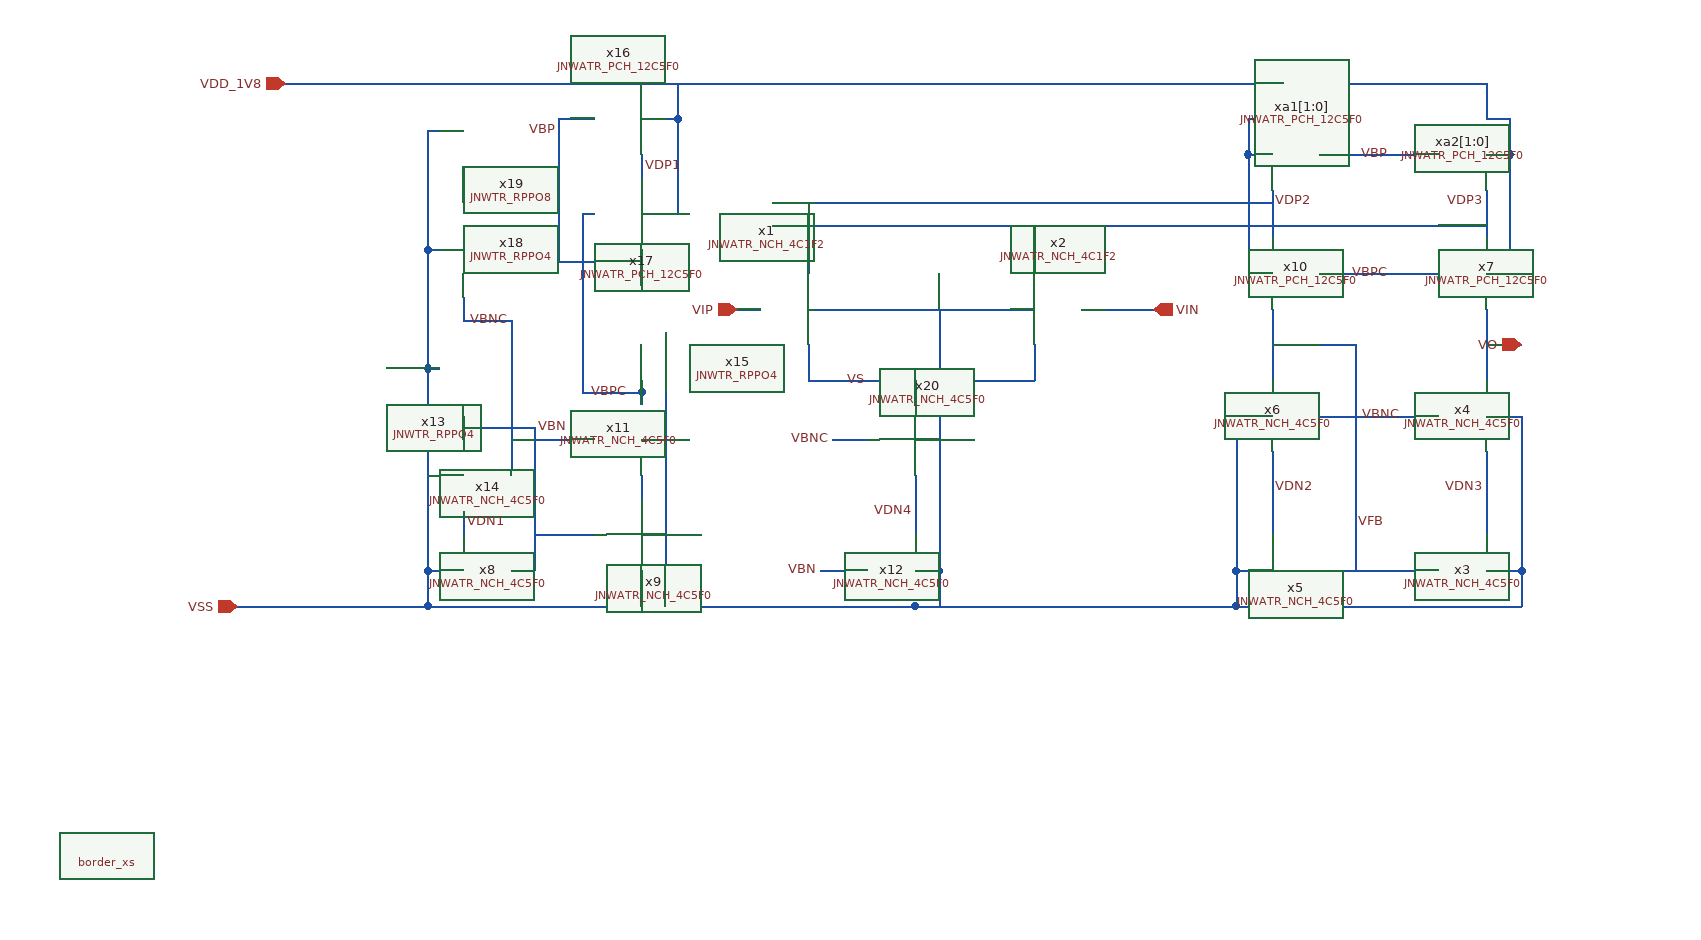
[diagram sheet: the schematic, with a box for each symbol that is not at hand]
v {xschem version=3.4.8RC file_version=1.3}
G {}
K {}
V {}
S {}
F {}
E {}
N 590 -460 780 -460 {lab=VSS}
N 1160 -240 1190 -240 {lab=VSS}
N 1190 -240 1190 -210 {lab=VSS}
N 1160 -210 1190 -210 {lab=VSS}
N 1160 -340 1160 -270 {lab=VDN3}
N 1160 -370 1190 -370 {lab=VSS}
N 1190 -370 1190 -240 {lab=VSS}
N 950 -240 980 -240 {lab=VSS}
N 950 -240 950 -210 {lab=VSS}
N 950 -210 980 -210 {lab=VSS}
N 980 -340 980 -270 {lab=VDN2}
N 950 -370 980 -370 {lab=VSS}
N 950 -370 950 -240 {lab=VSS}
N 1020 -370 1120 -370 {lab=VBNC}
N 1020 -240 1120 -240 {lab=VFB}
N 980 -210 1160 -210 {lab=VSS}
N 1160 -560 1160 -520 {lab=VDP3}
N 1160 -490 1180 -490 {lab=VDD_1V8}
N 1180 -590 1180 -490 {lab=VDD_1V8}
N 1160 -590 1180 -590 {lab=VDD_1V8}
N 1180 -620 1180 -590 {lab=VDD_1V8}
N 1160 -620 1180 -620 {lab=VDD_1V8}
N 980 -560 980 -520 {lab=VDP2}
N 960 -490 980 -490 {lab=VDD_1V8}
N 960 -590 960 -490 {lab=VDD_1V8}
N 960 -590 980 -590 {lab=VDD_1V8}
N 960 -620 960 -590 {lab=VDD_1V8}
N 960 -620 980 -620 {lab=VDD_1V8}
N 980 -460 980 -410 {lab=VFB}
N 1160 -460 1160 -400 {lab=VO}
N 1020 -590 1120 -590 {lab=VBP}
N 1020 -490 1120 -490 {lab=VBPC}
N 980 -410 980 -400 {lab=VFB}
N 1050 -430 1050 -240 {lab=VFB}
N 980 -430 1050 -430 {lab=VFB}
N 780 -430 780 -400 {lab=VS}
N 590 -400 780 -400 {lab=VS}
N 590 -430 590 -400 {lab=VS}
N 680 -240 700 -240 {lab=VSS}
N 700 -240 700 -210 {lab=VSS}
N 680 -210 700 -210 {lab=VSS}
N 680 -210 950 -210 {lab=VSS}
N 700 -460 700 -240 {lab=VSS}
N 820 -460 860 -460 {lab=VIN}
N 980 -650 980 -620 {lab=VDD_1V8}
N 980 -650 1160 -650 {lab=VDD_1V8}
N 1160 -650 1160 -620 {lab=VDD_1V8}
N 150 -650 990 -650 {lab=VDD_1V8}
N 270 -240 300 -240 {lab=VSS}
N 270 -240 270 -210 {lab=VSS}
N 270 -210 300 -210 {lab=VSS}
N 300 -210 680 -210 {lab=VSS}
N 270 -410 280 -410 {lab=VSS}
N 270 -410 270 -240 {lab=VSS}
N 300 -290 300 -270 {lab=VDN1}
N 270 -320 300 -320 {lab=VSS}
N 300 -370 300 -350 {lab=VBN}
N 300 -360 360 -360 {lab=VBN}
N 360 -360 360 -240 {lab=VBN}
N 340 -240 360 -240 {lab=VBN}
N 340 -450 340 -320 {lab=VBNC}
N 300 -450 340 -450 {lab=VBNC}
N 450 -510 450 -480 {lab=VBP}
N 450 -540 480 -540 {lab=VDD_1V8}
N 480 -620 480 -540 {lab=VDD_1V8}
N 450 -620 480 -620 {lab=VDD_1V8}
N 450 -590 450 -570 {lab=VDP1}
N 380 -620 410 -620 {lab=VBP}
N 450 -400 450 -390 {lab=VBPC}
N 380 -500 450 -500 {lab=VBP}
N 380 -620 380 -500 {lab=VBP}
N 400 -540 410 -540 {lab=VBPC}
N 400 -540 400 -390 {lab=VBPC}
N 400 -390 450 -390 {lab=VBPC}
N 300 -470 300 -450 {lab=VBNC}
N 270 -510 280 -510 {lab=VSS}
N 270 -510 270 -410 {lab=VSS}
N 470 -440 470 -210 {lab=VSS}
N 110 -210 270 -210 {lab=VSS}
N 530 -460 550 -460 {lab=VIP}
N 860 -460 880 -460 {lab=VIN}
N 1160 -430 1190 -430 {lab=VO}
N 600 -240 640 -240 {lab=VBN}
N 450 -240 450 -210 {lab=VSS}
N 360 -270 410 -270 {lab=VBN}
N 450 -270 470 -270 {lab=VSS}
N 560 -550 980 -550 {lab=VDP2}
N 560 -530 1160 -530 {lab=VDP3}
N 780 -530 780 -490 {lab=VDP3}
N 590 -550 590 -490 {lab=VDP2}
N 450 -350 470 -350 {lab=VSS}
N 450 -320 450 -300 {lab=#net1}
N 450 -390 450 -380 {lab=VBPC}
N 340 -350 410 -350 {lab=VBNC}
N 480 -650 480 -620 {lab=VDD_1V8}
N 300 -570 300 -550 {lab=#net2}
N 270 -610 270 -510 {lab=VSS}
N 270 -610 280 -610 {lab=VSS}
N 680 -350 700 -350 {lab=VSS}
N 680 -320 680 -270 {lab=VDN4}
N 680 -400 680 -380 {lab=VS}
N 610 -350 640 -350 {lab=VBNC}
C {cborder/border_xs.sym} 0 0 0 0 {
user="Carsten Wulff"
company="Carsten Wulff Software"}
C {devices/ipin.sym} 150 -650 0 0 {name=p1 lab=VDD_1V8}
C {devices/ipin.sym} 110 -210 0 0 {name=p2 lab=VSS}
C {JNW_ATR_SKY130A/JNWATR_NCH_4C1F2.sym} 550 -460 0 0 {name=x1 }
C {JNW_ATR_SKY130A/JNWATR_NCH_4C1F2.sym} 820 -460 0 1 {name=x2 }
C {JNW_ATR_SKY130A/JNWATR_NCH_4C5F0.sym} 1120 -240 0 0 {name=x3 }
C {JNW_ATR_SKY130A/JNWATR_NCH_4C5F0.sym} 1120 -370 0 0 {name=x4 }
C {JNW_ATR_SKY130A/JNWATR_NCH_4C5F0.sym} 1020 -240 0 1 {name=x5 }
C {JNW_ATR_SKY130A/JNWATR_NCH_4C5F0.sym} 1020 -370 0 1 {name=x6 }
C {JNW_ATR_SKY130A/JNWATR_PCH_12C5F0.sym} 1120 -490 0 0 {name=x7 }
C {JNW_ATR_SKY130A/JNWATR_PCH_12C5F0.sym} 1120 -590 0 0 {name=xa2[1:0] }
C {JNW_ATR_SKY130A/JNWATR_PCH_12C5F0.sym} 1020 -490 0 1 {name=x10 }
C {JNW_ATR_SKY130A/JNWATR_PCH_12C5F0.sym} 1020 -590 0 1 {name=xa1[1:0] }
C {JNW_ATR_SKY130A/JNWATR_NCH_4C5F0.sym} 640 -240 0 0 {name=x12 }
C {JNW_ATR_SKY130A/JNWATR_NCH_4C5F0.sym} 340 -240 0 1 {name=x8 }
C {JNW_TR_SKY130A/JNWTR_RPPO4.sym} 300 -370 1 1 {name=x13 }
C {JNW_ATR_SKY130A/JNWATR_NCH_4C5F0.sym} 340 -320 0 1 {name=x14 }
C {JNW_TR_SKY130A/JNWTR_RPPO4.sym} 450 -400 3 0 {name=x15 }
C {JNW_ATR_SKY130A/JNWATR_PCH_12C5F0.sym} 410 -620 0 0 {name=x16 }
C {JNW_ATR_SKY130A/JNWATR_PCH_12C5F0.sym} 410 -540 0 0 {name=x17 }
C {JNW_TR_SKY130A/JNWTR_RPPO4.sym} 300 -470 1 1 {name=x18 }
C {devices/lab_wire.sym} 440 -390 0 0 {name=p4 sig_type=std_logic lab=VBPC}
C {devices/lab_wire.sym} 340 -450 0 0 {name=p5 sig_type=std_logic lab=VBNC}
C {devices/lab_wire.sym} 360 -360 0 1 {name=p6 sig_type=std_logic lab=VBN
}
C {devices/lab_wire.sym} 380 -610 0 0 {name=p7 sig_type=std_logic lab=VBP}
C {devices/ipin.sym} 530 -460 0 0 {name=p3 lab=VIP}
C {devices/iopin.sym} 880 -460 2 1 {name=p8 lab=VIN}
C {devices/opin.sym} 1190 -430 2 1 {name=p9 lab=VO}
C {devices/lab_wire.sym} 600 -240 0 0 {name=p10 sig_type=std_logic lab=VBN
}
C {devices/lab_wire.sym} 1090 -370 0 0 {name=p11 sig_type=std_logic lab=VBNC
}
C {devices/lab_wire.sym} 1080 -590 0 0 {name=p12 sig_type=std_logic lab=VBP}
C {devices/lab_wire.sym} 1080 -490 0 0 {name=p13 sig_type=std_logic lab=VBPC}
C {devices/lab_wire.sym} 300 -280 0 1 {name=p14 sig_type=std_logic lab=VDN1}
C {devices/lab_wire.sym} 450 -580 0 1 {name=p15 sig_type=std_logic lab=VDP1}
C {devices/lab_wire.sym} 980 -550 0 1 {name=p16 sig_type=std_logic lab=VDP2}
C {devices/lab_wire.sym} 1160 -550 0 0 {name=p17 sig_type=std_logic lab=VDP3}
C {devices/lab_wire.sym} 980 -310 0 1 {name=p18 sig_type=std_logic lab=VDN2}
C {devices/lab_wire.sym} 1160 -310 0 0 {name=p19 sig_type=std_logic lab=VDN3}
C {devices/lab_wire.sym} 620 -400 0 1 {name=p20 sig_type=std_logic lab=VS}
C {JNW_ATR_SKY130A/JNWATR_NCH_4C5F0.sym} 410 -270 0 0 {name=x9 }
C {devices/lab_wire.sym} 1050 -280 0 1 {name=p21 sig_type=std_logic lab=VFB
}
C {JNW_ATR_SKY130A/JNWATR_NCH_4C5F0.sym} 410 -350 0 0 {name=x11 }
C {JNW_TR_SKY130A/JNWTR_RPPO8.sym} 300 -570 1 1 {name=x19 }
C {JNW_ATR_SKY130A/JNWATR_NCH_4C5F0.sym} 640 -350 0 0 {name=x20 }
C {devices/lab_wire.sym} 610 -350 0 0 {name=p22 sig_type=std_logic lab=VBNC}
C {devices/lab_wire.sym} 680 -290 0 0 {name=p23 sig_type=std_logic lab=VDN4}
